VERSION 5.7 ;
  NOWIREEXTENSIONATPIN ON ;
  DIVIDERCHAR "/" ;
  BUSBITCHARS "[]" ;
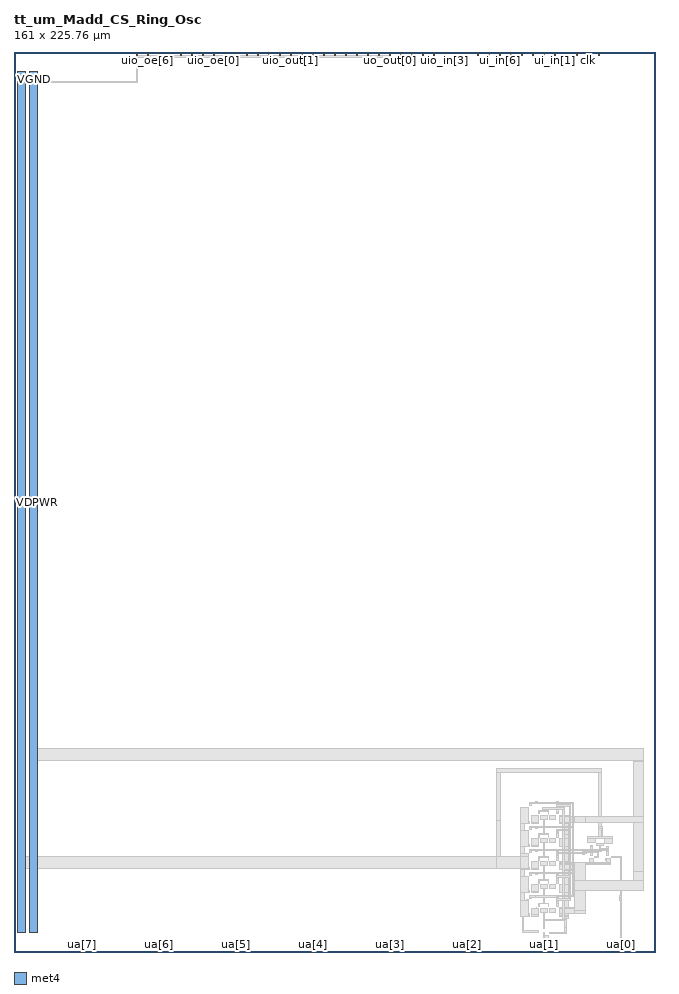
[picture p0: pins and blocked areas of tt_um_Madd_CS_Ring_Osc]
MACRO tt_um_Madd_CS_Ring_Osc
  CLASS BLOCK ;
  FOREIGN tt_um_Madd_CS_Ring_Osc ;
  ORIGIN 0.000 0.000 ;
  SIZE 161.000 BY 225.760 ;
  PIN clk
    DIRECTION INPUT ;
    USE SIGNAL ;
    PORT
      LAYER met4 ;
        RECT 143.830 224.760 144.130 225.760 ;
    END
  END clk
  PIN ena
    DIRECTION INPUT ;
    USE SIGNAL ;
    PORT
      LAYER met4 ;
        RECT 146.590 224.760 146.890 225.760 ;
    END
  END ena
  PIN rst_n
    DIRECTION INPUT ;
    USE SIGNAL ;
    PORT
      LAYER met4 ;
        RECT 141.070 224.760 141.370 225.760 ;
    END
  END rst_n
  PIN ua[3]
    DIRECTION INOUT ;
    USE SIGNAL ;
    PORT
      LAYER met4 ;
        RECT 93.850 0.000 94.750 1.000 ;
    END
  END ua[3]
  PIN ua[4]
    DIRECTION INOUT ;
    USE SIGNAL ;
    PORT
      LAYER met4 ;
        RECT 74.530 0.000 75.430 1.000 ;
    END
  END ua[4]
  PIN ua[5]
    DIRECTION INOUT ;
    USE SIGNAL ;
    PORT
      LAYER met4 ;
        RECT 55.210 0.000 56.110 1.000 ;
    END
  END ua[5]
  PIN ua[6]
    DIRECTION INOUT ;
    USE SIGNAL ;
    PORT
      LAYER met4 ;
        RECT 35.890 0.000 36.790 1.000 ;
    END
  END ua[6]
  PIN ua[7]
    DIRECTION INOUT ;
    USE SIGNAL ;
    PORT
      LAYER met4 ;
        RECT 16.570 0.000 17.470 1.000 ;
    END
  END ua[7]
  PIN ui_in[0]
    DIRECTION INPUT ;
    USE SIGNAL ;
    PORT
      LAYER met4 ;
        RECT 138.310 224.760 138.610 225.760 ;
    END
  END ui_in[0]
  PIN ui_in[1]
    DIRECTION INPUT ;
    USE SIGNAL ;
    PORT
      LAYER met4 ;
        RECT 135.550 224.760 135.850 225.760 ;
    END
  END ui_in[1]
  PIN ui_in[2]
    DIRECTION INPUT ;
    USE SIGNAL ;
    PORT
      LAYER met4 ;
        RECT 132.790 224.760 133.090 225.760 ;
    END
  END ui_in[2]
  PIN ui_in[3]
    DIRECTION INPUT ;
    USE SIGNAL ;
    PORT
      LAYER met4 ;
        RECT 130.030 224.760 130.330 225.760 ;
    END
  END ui_in[3]
  PIN ui_in[4]
    DIRECTION INPUT ;
    USE SIGNAL ;
    PORT
      LAYER met4 ;
        RECT 127.270 224.760 127.570 225.760 ;
    END
  END ui_in[4]
  PIN ui_in[5]
    DIRECTION INPUT ;
    USE SIGNAL ;
    PORT
      LAYER met4 ;
        RECT 124.510 224.760 124.810 225.760 ;
    END
  END ui_in[5]
  PIN ui_in[6]
    DIRECTION INPUT ;
    USE SIGNAL ;
    PORT
      LAYER met4 ;
        RECT 121.750 224.760 122.050 225.760 ;
    END
  END ui_in[6]
  PIN ui_in[7]
    DIRECTION INPUT ;
    USE SIGNAL ;
    PORT
      LAYER met4 ;
        RECT 118.990 224.760 119.290 225.760 ;
    END
  END ui_in[7]
  PIN uio_in[0]
    DIRECTION INPUT ;
    USE SIGNAL ;
    PORT
      LAYER met4 ;
        RECT 116.230 224.760 116.530 225.760 ;
    END
  END uio_in[0]
  PIN uio_in[1]
    DIRECTION INPUT ;
    USE SIGNAL ;
    PORT
      LAYER met4 ;
        RECT 113.470 224.760 113.770 225.760 ;
    END
  END uio_in[1]
  PIN uio_in[2]
    DIRECTION INPUT ;
    USE SIGNAL ;
    PORT
      LAYER met4 ;
        RECT 110.710 224.760 111.010 225.760 ;
    END
  END uio_in[2]
  PIN uio_in[3]
    DIRECTION INPUT ;
    USE SIGNAL ;
    PORT
      LAYER met4 ;
        RECT 107.950 224.760 108.250 225.760 ;
    END
  END uio_in[3]
  PIN uio_in[4]
    DIRECTION INPUT ;
    USE SIGNAL ;
    PORT
      LAYER met4 ;
        RECT 105.190 224.760 105.490 225.760 ;
    END
  END uio_in[4]
  PIN uio_in[5]
    DIRECTION INPUT ;
    USE SIGNAL ;
    PORT
      LAYER met4 ;
        RECT 102.430 224.760 102.730 225.760 ;
    END
  END uio_in[5]
  PIN uio_in[6]
    DIRECTION INPUT ;
    USE SIGNAL ;
    PORT
      LAYER met4 ;
        RECT 99.670 224.760 99.970 225.760 ;
    END
  END uio_in[6]
  PIN uio_in[7]
    DIRECTION INPUT ;
    USE SIGNAL ;
    PORT
      LAYER met4 ;
        RECT 96.910 224.760 97.210 225.760 ;
    END
  END uio_in[7]
  PIN uio_oe[0]
    DIRECTION OUTPUT ;
    USE SIGNAL ;
    PORT
      LAYER met4 ;
        RECT 49.990 224.760 50.290 225.760 ;
    END
  END uio_oe[0]
  PIN uio_oe[1]
    DIRECTION OUTPUT ;
    USE SIGNAL ;
    PORT
      LAYER met4 ;
        RECT 47.230 224.760 47.530 225.760 ;
    END
  END uio_oe[1]
  PIN uio_oe[2]
    DIRECTION OUTPUT ;
    USE SIGNAL ;
    PORT
      LAYER met4 ;
        RECT 44.470 224.760 44.770 225.760 ;
    END
  END uio_oe[2]
  PIN uio_oe[3]
    DIRECTION OUTPUT ;
    USE SIGNAL ;
    PORT
      LAYER met4 ;
        RECT 41.710 224.760 42.010 225.760 ;
    END
  END uio_oe[3]
  PIN uio_oe[4]
    DIRECTION OUTPUT ;
    USE SIGNAL ;
    PORT
      LAYER met4 ;
        RECT 38.950 224.760 39.250 225.760 ;
    END
  END uio_oe[4]
  PIN uio_oe[5]
    DIRECTION OUTPUT ;
    USE SIGNAL ;
    PORT
      LAYER met4 ;
        RECT 36.190 224.760 36.490 225.760 ;
    END
  END uio_oe[5]
  PIN uio_oe[6]
    DIRECTION OUTPUT ;
    USE SIGNAL ;
    PORT
      LAYER met4 ;
        RECT 33.430 224.760 33.730 225.760 ;
    END
  END uio_oe[6]
  PIN uio_oe[7]
    DIRECTION OUTPUT ;
    USE SIGNAL ;
    PORT
      LAYER met4 ;
        RECT 30.670 224.760 30.970 225.760 ;
    END
  END uio_oe[7]
  PIN uio_out[0]
    DIRECTION OUTPUT ;
    USE SIGNAL ;
    PORT
      LAYER met4 ;
        RECT 72.070 224.760 72.370 225.760 ;
    END
  END uio_out[0]
  PIN uio_out[1]
    DIRECTION OUTPUT ;
    USE SIGNAL ;
    PORT
      LAYER met4 ;
        RECT 69.310 224.760 69.610 225.760 ;
    END
  END uio_out[1]
  PIN uio_out[2]
    DIRECTION OUTPUT ;
    USE SIGNAL ;
    PORT
      LAYER met4 ;
        RECT 66.550 224.760 66.850 225.760 ;
    END
  END uio_out[2]
  PIN uio_out[3]
    DIRECTION OUTPUT ;
    USE SIGNAL ;
    PORT
      LAYER met4 ;
        RECT 63.790 224.760 64.090 225.760 ;
    END
  END uio_out[3]
  PIN uio_out[4]
    DIRECTION OUTPUT ;
    USE SIGNAL ;
    PORT
      LAYER met4 ;
        RECT 61.030 224.760 61.330 225.760 ;
    END
  END uio_out[4]
  PIN uio_out[5]
    DIRECTION OUTPUT ;
    USE SIGNAL ;
    PORT
      LAYER met4 ;
        RECT 58.270 224.760 58.570 225.760 ;
    END
  END uio_out[5]
  PIN uio_out[6]
    DIRECTION OUTPUT ;
    USE SIGNAL ;
    PORT
      LAYER met4 ;
        RECT 55.510 224.760 55.810 225.760 ;
    END
  END uio_out[6]
  PIN uio_out[7]
    DIRECTION OUTPUT ;
    USE SIGNAL ;
    PORT
      LAYER met4 ;
        RECT 52.750 224.760 53.050 225.760 ;
    END
  END uio_out[7]
  PIN uo_out[0]
    DIRECTION OUTPUT ;
    USE SIGNAL ;
    PORT
      LAYER met4 ;
        RECT 94.150 224.760 94.450 225.760 ;
    END
  END uo_out[0]
  PIN uo_out[1]
    DIRECTION OUTPUT ;
    USE SIGNAL ;
    PORT
      LAYER met4 ;
        RECT 91.390 224.760 91.690 225.760 ;
    END
  END uo_out[1]
  PIN uo_out[2]
    DIRECTION OUTPUT ;
    USE SIGNAL ;
    PORT
      LAYER met4 ;
        RECT 88.630 224.760 88.930 225.760 ;
    END
  END uo_out[2]
  PIN uo_out[3]
    DIRECTION OUTPUT ;
    USE SIGNAL ;
    PORT
      LAYER met4 ;
        RECT 85.870 224.760 86.170 225.760 ;
    END
  END uo_out[3]
  PIN uo_out[4]
    DIRECTION OUTPUT ;
    USE SIGNAL ;
    PORT
      LAYER met4 ;
        RECT 83.110 224.760 83.410 225.760 ;
    END
  END uo_out[4]
  PIN uo_out[5]
    DIRECTION OUTPUT ;
    USE SIGNAL ;
    PORT
      LAYER met4 ;
        RECT 80.350 224.760 80.650 225.760 ;
    END
  END uo_out[5]
  PIN uo_out[6]
    DIRECTION OUTPUT ;
    USE SIGNAL ;
    PORT
      LAYER met4 ;
        RECT 77.590 224.760 77.890 225.760 ;
    END
  END uo_out[6]
  PIN uo_out[7]
    DIRECTION OUTPUT ;
    USE SIGNAL ;
    PORT
      LAYER met4 ;
        RECT 74.830 224.760 75.130 225.760 ;
    END
  END uo_out[7]
  PIN VDPWR
    DIRECTION INOUT ;
    USE POWER ;
    PORT
      LAYER met4 ;
        RECT 1.000 5.000 3.000 220.760 ;
    END
  END VDPWR
  PIN VGND
    DIRECTION INOUT ;
    USE GROUND ;
    PORT
      LAYER met4 ;
        RECT 4.000 5.000 6.000 220.760 ;
    END
  END VGND
  PIN ua[2]
    DIRECTION INOUT ;
    USE ANALOG ;
    PORT
      LAYER met4 ;
        RECT 113.170 0.000 114.040 0.990 ;
    END
  END ua[2]
  PIN ua[1]
    DIRECTION INOUT ;
    USE ANALOG ;
    PORT
      LAYER met4 ;
        RECT 132.490 0.000 133.360 0.940 ;
    END
  END ua[1]
  PIN ua[0]
    DIRECTION INOUT ;
    USE ANALOG ;
    PORT
      LAYER met4 ;
        RECT 151.810 0.000 152.680 0.990 ;
    END
  END ua[0]
  OBS
      LAYER pwell ;
        RECT 133.150 4.030 134.030 4.040 ;
        RECT 133.110 3.110 134.030 4.030 ;
        RECT 133.110 3.100 133.990 3.110 ;
      LAYER li1 ;
        RECT 128.580 32.790 129.150 36.250 ;
        RECT 130.980 34.200 131.020 34.250 ;
        RECT 128.580 32.210 129.210 32.790 ;
        RECT 130.990 32.210 131.020 34.200 ;
        RECT 136.730 32.210 137.310 34.250 ;
        RECT 128.575 26.985 129.145 30.445 ;
        RECT 130.975 28.395 131.015 28.445 ;
        RECT 128.575 26.405 129.205 26.985 ;
        RECT 130.985 26.405 131.015 28.395 ;
        RECT 136.725 26.405 137.305 28.445 ;
        RECT 143.905 27.405 145.945 27.980 ;
        RECT 148.045 27.475 150.085 28.050 ;
        RECT 128.575 21.190 129.145 24.650 ;
        RECT 144.350 22.890 145.400 23.470 ;
        RECT 148.490 22.900 149.530 23.385 ;
        RECT 130.975 22.600 131.015 22.650 ;
        RECT 128.575 20.610 129.205 21.190 ;
        RECT 130.985 20.610 131.015 22.600 ;
        RECT 136.725 20.610 137.305 22.650 ;
        RECT 128.580 15.390 129.150 18.850 ;
        RECT 130.980 16.800 131.020 16.850 ;
        RECT 128.580 14.810 129.210 15.390 ;
        RECT 130.990 14.810 131.020 16.800 ;
        RECT 136.730 14.810 137.310 16.850 ;
        RECT 128.575 9.590 129.145 13.050 ;
        RECT 130.975 11.000 131.015 11.050 ;
        RECT 128.575 9.010 129.205 9.590 ;
        RECT 130.985 9.010 131.015 11.000 ;
        RECT 136.725 9.010 137.305 11.050 ;
        RECT 132.855 5.990 133.025 6.160 ;
        RECT 132.855 4.610 133.025 4.780 ;
      LAYER met1 ;
        RECT 130.795 37.600 131.305 37.700 ;
        RECT 129.400 37.300 131.305 37.600 ;
        RECT 129.400 36.665 129.700 37.300 ;
        RECT 130.795 37.200 131.305 37.300 ;
        RECT 129.400 36.655 129.415 36.665 ;
        RECT 136.100 36.500 136.600 37.000 ;
        RECT 136.200 36.480 136.505 36.500 ;
        RECT 126.985 32.230 129.030 36.230 ;
        RECT 132.685 35.770 133.185 36.270 ;
        RECT 136.200 36.200 136.500 36.480 ;
        RECT 132.785 35.470 133.085 35.770 ;
        RECT 131.690 35.320 134.190 35.470 ;
        RECT 131.690 34.620 131.840 35.320 ;
        RECT 134.040 34.570 134.190 35.320 ;
        RECT 136.200 35.105 136.510 36.200 ;
        RECT 136.205 34.635 136.510 35.105 ;
        RECT 136.110 34.620 136.570 34.635 ;
        RECT 129.910 32.510 131.620 34.230 ;
        RECT 131.990 33.230 133.825 34.230 ;
        RECT 133.895 33.230 133.900 33.580 ;
        RECT 134.380 33.230 135.940 34.230 ;
        RECT 136.760 33.910 138.990 34.230 ;
        RECT 136.760 33.900 141.605 33.910 ;
        RECT 129.900 32.230 131.640 32.510 ;
        RECT 126.985 30.425 127.990 32.230 ;
        RECT 130.800 31.500 131.300 31.600 ;
        RECT 129.400 31.200 131.300 31.500 ;
        RECT 129.400 30.800 129.700 31.200 ;
        RECT 130.800 31.100 131.300 31.200 ;
        RECT 126.985 26.425 129.025 30.425 ;
        RECT 132.785 29.665 133.085 33.230 ;
        RECT 136.760 32.400 143.395 33.900 ;
        RECT 136.760 32.270 138.990 32.400 ;
        RECT 136.770 32.230 138.990 32.270 ;
        RECT 131.685 29.515 134.185 29.665 ;
        RECT 136.095 29.600 136.595 30.100 ;
        RECT 131.685 28.815 131.835 29.515 ;
        RECT 134.035 28.765 134.185 29.515 ;
        RECT 136.200 28.800 136.505 29.600 ;
        RECT 137.990 29.365 138.990 32.230 ;
        RECT 137.985 28.425 138.990 29.365 ;
        RECT 146.500 31.005 147.495 31.115 ;
        RECT 129.905 26.705 131.615 28.425 ;
        RECT 131.985 27.425 133.820 28.425 ;
        RECT 133.890 27.425 133.895 27.775 ;
        RECT 134.375 27.425 135.935 28.425 ;
        RECT 129.895 26.425 131.635 26.705 ;
        RECT 126.985 24.630 127.990 26.425 ;
        RECT 130.800 25.700 131.300 25.800 ;
        RECT 129.400 25.400 131.300 25.700 ;
        RECT 129.400 25.000 129.700 25.400 ;
        RECT 130.800 25.300 131.300 25.400 ;
        RECT 126.985 24.000 129.025 24.630 ;
        RECT 121.000 21.000 129.025 24.000 ;
        RECT 132.785 23.870 133.085 27.425 ;
        RECT 136.755 26.465 138.990 28.425 ;
        RECT 143.925 28.970 145.925 28.975 ;
        RECT 146.500 28.970 147.500 31.005 ;
        RECT 148.065 28.975 150.030 28.980 ;
        RECT 148.065 28.970 150.065 28.975 ;
        RECT 143.925 28.480 150.065 28.970 ;
        RECT 143.925 27.400 145.925 28.480 ;
        RECT 148.065 27.300 150.065 28.480 ;
        RECT 146.130 26.795 147.860 27.255 ;
        RECT 136.765 26.425 138.990 26.465 ;
        RECT 131.685 23.720 134.185 23.870 ;
        RECT 136.095 23.800 136.595 24.300 ;
        RECT 131.685 23.020 131.835 23.720 ;
        RECT 134.035 22.970 134.185 23.720 ;
        RECT 136.200 23.015 136.505 23.800 ;
        RECT 136.105 23.000 136.565 23.015 ;
        RECT 137.985 22.630 138.990 26.425 ;
        RECT 144.545 26.515 145.045 26.670 ;
        RECT 144.545 25.200 145.040 26.515 ;
        RECT 146.845 25.875 147.145 26.795 ;
        RECT 148.745 25.875 149.245 26.575 ;
        RECT 146.845 25.800 149.245 25.875 ;
        RECT 146.800 25.575 149.245 25.800 ;
        RECT 146.800 25.300 147.300 25.575 ;
        RECT 143.200 25.160 145.040 25.200 ;
        RECT 148.745 25.160 149.245 25.575 ;
        RECT 142.485 24.900 142.985 25.005 ;
        RECT 143.200 24.900 146.650 25.160 ;
        RECT 142.485 24.600 143.500 24.900 ;
        RECT 144.545 24.870 146.650 24.900 ;
        RECT 142.485 24.505 142.985 24.600 ;
        RECT 144.545 24.330 145.050 24.870 ;
        RECT 144.550 24.290 145.050 24.330 ;
        RECT 146.350 23.985 146.650 24.870 ;
        RECT 148.750 24.265 149.250 25.160 ;
        RECT 145.650 23.680 146.655 23.985 ;
        RECT 149.805 23.700 152.400 24.000 ;
        RECT 126.985 20.630 129.025 21.000 ;
        RECT 129.905 20.910 131.615 22.630 ;
        RECT 131.985 21.630 133.820 22.630 ;
        RECT 133.890 21.630 133.895 21.980 ;
        RECT 134.375 21.630 135.935 22.630 ;
        RECT 136.755 22.510 138.990 22.630 ;
        RECT 144.375 22.515 145.375 23.540 ;
        RECT 149.420 23.490 149.510 23.535 ;
        RECT 140.245 22.510 145.375 22.515 ;
        RECT 136.755 22.470 145.375 22.510 ;
        RECT 148.510 22.470 149.510 23.490 ;
        RECT 136.755 22.105 149.510 22.470 ;
        RECT 136.755 21.960 149.515 22.105 ;
        RECT 129.895 20.630 131.635 20.910 ;
        RECT 126.985 18.830 127.990 20.630 ;
        RECT 130.805 19.890 131.305 19.990 ;
        RECT 129.405 19.590 131.305 19.890 ;
        RECT 129.405 19.190 129.705 19.590 ;
        RECT 130.805 19.490 131.305 19.590 ;
        RECT 126.985 14.830 129.030 18.830 ;
        RECT 132.785 18.070 133.085 21.630 ;
        RECT 136.755 20.670 143.420 21.960 ;
        RECT 136.765 20.630 143.420 20.670 ;
        RECT 137.985 20.495 143.420 20.630 ;
        RECT 137.985 20.485 140.910 20.495 ;
        RECT 131.690 17.920 134.190 18.070 ;
        RECT 136.100 18.000 136.600 18.500 ;
        RECT 131.690 17.220 131.840 17.920 ;
        RECT 134.040 17.170 134.190 17.920 ;
        RECT 136.205 17.215 136.510 18.000 ;
        RECT 136.110 17.200 136.570 17.215 ;
        RECT 137.985 16.830 138.990 20.485 ;
        RECT 129.910 15.110 131.620 16.830 ;
        RECT 131.990 15.830 133.825 16.830 ;
        RECT 133.895 15.830 133.900 16.180 ;
        RECT 134.380 15.830 135.940 16.830 ;
        RECT 129.900 14.830 131.640 15.110 ;
        RECT 126.985 13.030 127.990 14.830 ;
        RECT 130.800 14.090 131.300 14.190 ;
        RECT 129.400 13.790 131.300 14.090 ;
        RECT 129.400 13.390 129.700 13.790 ;
        RECT 130.800 13.690 131.300 13.790 ;
        RECT 126.985 9.030 129.025 13.030 ;
        RECT 132.785 12.270 133.085 15.830 ;
        RECT 136.760 14.870 138.990 16.830 ;
        RECT 136.770 14.830 138.990 14.870 ;
        RECT 137.985 14.270 138.990 14.830 ;
        RECT 131.685 12.120 134.185 12.270 ;
        RECT 136.095 12.195 136.595 12.695 ;
        RECT 131.685 11.420 131.835 12.120 ;
        RECT 134.035 11.370 134.185 12.120 ;
        RECT 136.200 11.415 136.505 12.195 ;
        RECT 136.105 11.400 136.565 11.415 ;
        RECT 137.985 11.110 138.985 14.270 ;
        RECT 152.100 14.200 152.400 23.700 ;
        RECT 152.000 13.700 152.500 14.200 ;
        RECT 137.985 11.105 141.400 11.110 ;
        RECT 137.985 11.030 143.390 11.105 ;
        RECT 129.905 9.310 131.615 11.030 ;
        RECT 131.985 10.030 133.820 11.030 ;
        RECT 133.890 10.030 133.895 10.380 ;
        RECT 134.375 10.030 135.935 11.030 ;
        RECT 129.895 9.030 131.635 9.310 ;
        RECT 127.500 7.015 127.900 9.030 ;
        RECT 132.785 8.320 133.085 10.030 ;
        RECT 136.755 9.605 143.390 11.030 ;
        RECT 136.755 9.600 141.400 9.605 ;
        RECT 136.755 9.070 138.985 9.600 ;
        RECT 136.765 9.030 138.985 9.070 ;
        RECT 137.985 8.470 138.985 9.030 ;
        RECT 132.735 7.920 133.135 8.320 ;
        RECT 138.200 8.105 138.600 8.470 ;
        RECT 127.500 5.280 127.885 7.015 ;
        RECT 132.835 6.270 133.035 7.920 ;
        RECT 132.785 5.920 133.085 6.270 ;
        RECT 138.200 6.095 138.605 8.105 ;
        RECT 127.500 4.900 131.550 5.280 ;
        RECT 138.200 5.005 138.600 6.095 ;
        RECT 132.785 4.520 133.085 4.870 ;
        RECT 134.215 4.605 138.600 5.005 ;
        RECT 132.850 2.805 133.050 4.520 ;
        RECT 132.500 2.700 133.400 2.805 ;
        RECT 132.500 2.300 133.405 2.700 ;
      LAYER met2 ;
        RECT 120.995 45.000 147.485 46.000 ;
        RECT 120.995 33.005 121.995 45.000 ;
        RECT 130.795 37.600 131.305 37.700 ;
        RECT 136.100 37.600 136.600 37.700 ;
        RECT 130.795 37.300 136.600 37.600 ;
        RECT 130.795 37.200 131.305 37.300 ;
        RECT 136.100 37.200 136.600 37.300 ;
        RECT 136.100 36.895 136.600 37.000 ;
        RECT 139.300 36.895 139.600 36.900 ;
        RECT 136.100 36.595 139.600 36.895 ;
        RECT 136.100 36.500 136.600 36.595 ;
        RECT 132.685 36.170 133.185 36.270 ;
        RECT 132.685 35.870 137.985 36.170 ;
        RECT 132.685 35.770 133.185 35.870 ;
        RECT 120.990 24.000 122.000 33.005 ;
        RECT 130.800 31.500 131.300 31.600 ;
        RECT 136.100 31.500 136.600 31.600 ;
        RECT 130.800 31.200 136.600 31.500 ;
        RECT 130.800 31.100 131.300 31.200 ;
        RECT 136.100 31.105 136.600 31.200 ;
        RECT 136.095 30.300 136.600 30.800 ;
        RECT 136.195 30.100 136.500 30.300 ;
        RECT 136.095 29.600 136.595 30.100 ;
        RECT 130.800 25.700 131.300 25.800 ;
        RECT 136.100 25.700 136.600 25.800 ;
        RECT 130.800 25.400 136.600 25.700 ;
        RECT 130.800 25.300 131.300 25.400 ;
        RECT 136.100 25.300 136.600 25.400 ;
        RECT 136.095 24.500 136.600 25.000 ;
        RECT 136.195 24.300 136.500 24.500 ;
        RECT 115.000 21.000 126.985 24.000 ;
        RECT 136.095 23.800 136.595 24.300 ;
        RECT 130.805 19.900 131.305 19.990 ;
        RECT 136.100 19.900 136.605 20.000 ;
        RECT 130.805 19.600 136.605 19.900 ;
        RECT 130.805 19.490 131.305 19.600 ;
        RECT 136.100 19.500 136.605 19.600 ;
        RECT 136.100 18.700 136.605 19.200 ;
        RECT 136.200 18.500 136.505 18.700 ;
        RECT 136.100 18.000 136.600 18.500 ;
        RECT 130.800 14.100 131.300 14.190 ;
        RECT 136.100 14.100 136.600 14.200 ;
        RECT 130.800 13.795 136.600 14.100 ;
        RECT 130.800 13.690 131.300 13.795 ;
        RECT 136.100 13.700 136.600 13.795 ;
        RECT 136.095 12.895 136.600 13.395 ;
        RECT 136.195 12.695 136.500 12.895 ;
        RECT 136.095 12.195 136.595 12.695 ;
        RECT 132.735 8.270 133.135 8.320 ;
        RECT 137.685 8.270 137.985 35.870 ;
        RECT 139.300 30.800 139.600 36.595 ;
        RECT 140.700 32.400 146.000 33.900 ;
        RECT 146.505 32.505 147.485 45.000 ;
        RECT 146.500 31.500 147.495 32.505 ;
        RECT 146.500 31.000 147.500 31.500 ;
        RECT 139.200 30.300 139.700 30.800 ;
        RECT 139.300 24.995 139.600 30.300 ;
        RECT 146.500 28.970 147.495 31.000 ;
        RECT 142.495 25.700 143.005 25.805 ;
        RECT 146.800 25.700 147.300 25.800 ;
        RECT 142.495 25.405 147.300 25.700 ;
        RECT 142.495 25.300 143.005 25.405 ;
        RECT 146.800 25.300 147.300 25.405 ;
        RECT 139.200 24.905 139.700 24.995 ;
        RECT 142.485 24.905 142.985 25.005 ;
        RECT 139.200 24.595 142.985 24.905 ;
        RECT 139.200 24.495 139.700 24.595 ;
        RECT 142.485 24.505 142.985 24.595 ;
        RECT 139.300 19.200 139.600 24.495 ;
        RECT 139.200 18.700 139.700 19.200 ;
        RECT 139.300 13.400 139.600 18.700 ;
        RECT 139.200 12.900 139.700 13.400 ;
        RECT 140.700 10.450 143.420 22.510 ;
        RECT 152.000 13.700 152.500 14.200 ;
        RECT 152.100 13.300 152.400 13.700 ;
        RECT 152.000 12.800 152.500 13.300 ;
        RECT 140.700 9.605 143.390 10.450 ;
        RECT 132.735 7.970 137.985 8.270 ;
        RECT 132.735 7.915 133.135 7.970 ;
        RECT 132.500 2.700 133.400 2.805 ;
        RECT 132.500 2.300 133.405 2.700 ;
        RECT 132.500 1.800 133.400 2.300 ;
      LAYER met3 ;
        RECT 4.000 51.000 6.000 51.005 ;
        RECT 30.010 51.000 158.010 51.005 ;
        RECT 4.000 48.000 158.010 51.000 ;
        RECT 5.000 47.995 35.010 48.000 ;
        RECT 155.500 47.780 158.010 48.000 ;
        RECT 136.100 37.600 136.600 37.700 ;
        RECT 136.100 37.300 140.300 37.600 ;
        RECT 136.100 37.200 136.600 37.300 ;
        RECT 136.100 31.500 136.600 31.600 ;
        RECT 140.000 31.500 140.300 37.300 ;
        RECT 155.500 33.900 158.030 47.780 ;
        RECT 143.400 32.400 158.030 33.900 ;
        RECT 136.100 31.200 140.300 31.500 ;
        RECT 136.100 31.105 136.600 31.200 ;
        RECT 136.095 30.700 136.600 30.800 ;
        RECT 139.200 30.700 139.700 30.800 ;
        RECT 136.095 30.400 139.700 30.700 ;
        RECT 136.095 30.300 136.600 30.400 ;
        RECT 139.200 30.300 139.700 30.400 ;
        RECT 136.100 25.700 136.600 25.800 ;
        RECT 140.000 25.700 140.300 31.200 ;
        RECT 142.495 25.700 143.005 25.805 ;
        RECT 136.100 25.400 143.005 25.700 ;
        RECT 136.100 25.300 136.600 25.400 ;
        RECT 136.095 24.900 136.600 25.000 ;
        RECT 139.200 24.900 139.700 24.995 ;
        RECT 136.095 24.600 139.700 24.900 ;
        RECT 136.095 24.500 136.600 24.600 ;
        RECT 139.200 24.495 139.700 24.600 ;
        RECT 1.000 23.990 32.005 24.000 ;
        RECT 112.000 23.990 121.000 24.000 ;
        RECT 1.000 21.010 121.000 23.990 ;
        RECT 1.000 20.995 32.005 21.010 ;
        RECT 112.000 21.000 121.000 21.010 ;
        RECT 112.000 20.970 115.000 21.000 ;
        RECT 136.100 19.900 136.605 20.000 ;
        RECT 140.000 19.900 140.300 25.400 ;
        RECT 142.495 25.300 143.005 25.400 ;
        RECT 136.100 19.600 140.300 19.900 ;
        RECT 136.100 19.500 136.605 19.600 ;
        RECT 136.100 19.100 136.605 19.200 ;
        RECT 139.200 19.100 139.700 19.200 ;
        RECT 136.100 18.800 139.700 19.100 ;
        RECT 136.100 18.700 136.605 18.800 ;
        RECT 139.200 18.700 139.700 18.800 ;
        RECT 136.100 14.100 136.600 14.200 ;
        RECT 140.000 14.100 140.300 19.600 ;
        RECT 155.500 20.130 158.030 32.400 ;
        RECT 140.710 17.995 148.010 18.010 ;
        RECT 155.500 17.995 158.000 20.130 ;
        RECT 140.710 15.510 158.000 17.995 ;
        RECT 140.990 15.495 158.000 15.510 ;
        RECT 140.990 15.480 148.010 15.495 ;
        RECT 136.100 13.800 140.300 14.100 ;
        RECT 136.100 13.700 136.600 13.800 ;
        RECT 136.095 13.300 136.600 13.395 ;
        RECT 139.200 13.300 139.700 13.400 ;
        RECT 136.095 13.000 139.700 13.300 ;
        RECT 136.095 12.895 136.600 13.000 ;
        RECT 139.200 12.900 139.700 13.000 ;
        RECT 152.000 12.800 152.500 13.300 ;
        RECT 132.500 1.500 133.400 2.300 ;
        RECT 152.100 2.200 152.400 12.800 ;
        RECT 132.490 1.000 133.400 1.500 ;
        RECT 151.800 1.000 152.700 2.200 ;
      LAYER met4 ;
        RECT 30.670 224.410 94.460 224.760 ;
        RECT 30.700 218.400 31.100 224.410 ;
        RECT 6.000 218.000 31.100 218.400 ;
        RECT 132.490 1.000 133.395 1.550 ;
        RECT 113.170 0.990 114.070 1.000 ;
        RECT 114.040 0.000 114.070 0.990 ;
        RECT 132.490 0.940 133.390 1.000 ;
        RECT 151.810 0.990 152.710 1.600 ;
        RECT 133.360 0.000 133.390 0.940 ;
        RECT 152.680 0.000 152.710 0.990 ;
  END
END tt_um_Madd_CS_Ring_Osc
END LIBRARY

